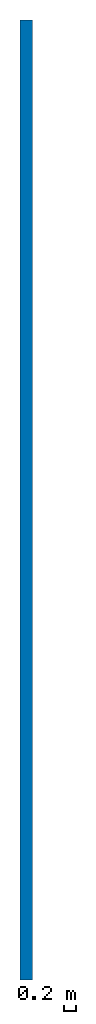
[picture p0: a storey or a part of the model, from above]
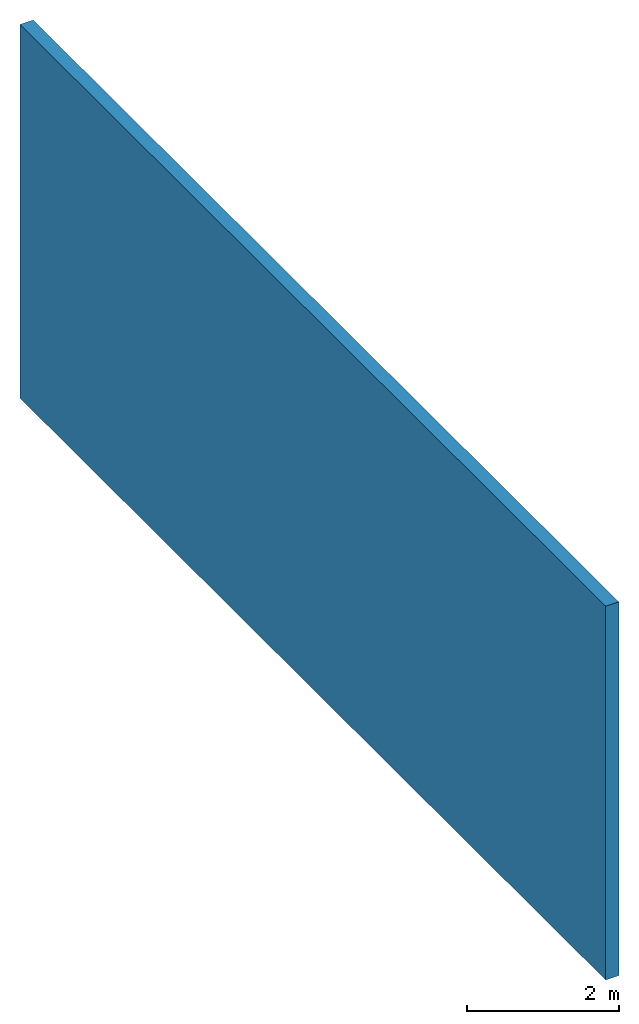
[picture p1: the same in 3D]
Properties of the parts of a building model (IFC2X3)

# File
Description: ViewDefinition [CoordinationView_V2.0]
File name: Project Number
Time: 2020-12-11T19:03:07
Written by: The EXPRESS Data Manager Version 5.02.0100.07 : 28 Aug 2013
Made in: 20190108_1515(x64) - Exporter 19.4.1.0 - Alternate UI 19.4.1.0
Comment: STEP Physical File produced by: The EXPRESS Data Manager Version 5.02.0100.07 : 28 Aug 2013 * Module: EDMstepFileFactory/EDMstandAlone * Creation date: Fri Dec 11 19:03:07 2020 * Host: OMEN-10 * Database: C:\Users\Eipm02\AppData\Local\Temp\{3D1B1A2C-8589-4297-B3EE-2A025A28AC27}\ifc * Database version: 5507 * Database creation date: Fri Dec 11 19:03:03 2020 * Schema: IFC2X3 * Model: DataRepository.ifc * Model creation date: Fri Dec 11 19:03:04 2020 * Header model: DataRepository.ifc_HeaderModel * Header model creation date: Fri Dec 11 19:03:04 2020 * EDMuser: sdai-user * EDMgroup: sdai-group * License ID and type: 5605 : Permanent license. Expiry date: * EDMstepFileFactory options: 020000

# IfcProject, Project Number
LongName: Project Name; Phase: Project Status

# IfcSite, Default
RefLatitude: 42, 21, 31, 181945; RefLongitude: -71, -3, -24, -263305; RefElevation: 57 m
Pset_ProductRequirements - Category: Project Information
Other - Category: Project Information; Client Name: Owner; Project Address: ## Street City, State Zip; Project Issue Date: Issue Date; Project Name: Project Name; Project Number: Project Number; Project Status: Project Status

# IfcBuilding
Pset_BuildingCommon - NumberOfStoreys: 2
Pset_ProductRequirements - Category: Project Information
Other - Category: Project Information; Client Name: Owner; Project Address: ## Street City, State Zip; Project Issue Date: Issue Date; Project Name: Project Name; Project Number: Project Number; Project Status: Project Status

# IfcBuildingStorey: Level:8mm Head (2)
Other(Type) - Category: Levels; Family Name: Level
Pset_ProductRequirements - Category: Levels
Dimensions - Computation Height: 0 m
Identity Data - Structural: no
Other - Category: Levels; Family: Level: 8mm Head; Family and Type: Level: 8mm Head; Type: Level: 8mm Head; Type Id: Level: 8mm Head
Constraints(Type) - Elevation Base: Project Base Point
Graphics(Type) - Color: 0; Line Pattern: Center; Line Weight: 1; Symbol: M_Level Head - Circle: M_Level Head - Circle; Symbol at End 1 Default: no; Symbol at End 2 Default: yes
Identity Data(Type) - Type Name: 8mm Head
Name | LongName | Elevation (m) | Pset_AirSideSystemInformation, Name = Pset_ProductRequirements, Name = Identity Data, Name | Constraints, Elevation (m) | Building Story
Level 1 | Level 1 | 1 | Altura interno | 2 | no
Level 2 | Level 2 | 7 | Level 2 | 9 | yes

# IfcWallStandardCase: Basic Wall:Generic - 200mm (2)
Type - PredefinedType: STANDARD; Material: Default Wall 0.2 m
Type - Analytical Properties - Absorptance: 0.1; Roughness: 1
Type - Construction - Function: Exterior; Width: 0.2 m; Wrapping at Inserts: Do not wrap
Type - Graphics - Coarse Scale Fill Color: 0
Type - Identity Data - Type Name: Generic - 200mm
Type - Other - Category: Walls; Family Name: Basic Wall
Type - Pset_ElementShading - Roughness: 0.3048 m
Type - Pset_ProductRequirements - Category: Walls
Type - Pset_QuantityTakeOff - Reference: Generic - 200mm
Type - Pset_ReinforcementBarPitchOfWall - Reference: Generic - 200mm
Type - Pset_WallCommon - Reference: Generic - 200mm; IsExternal: no
Constraints - Base Extension Distance: 0 m; Base is Attached: no; Base Offset: 0 m; Location Line: Wall Centerline; Related to Mass: no; Room Bounding: yes; Top Extension Distance: 0 m; Top is Attached: no; Top Offset: 0 m
Dimensions - Length: 15.4 m
Other - Family: Basic Wall: Generic - 200mm; Family and Type: Basic Wall: Generic - 200mm; Type: Basic Wall: Generic - 200mm; Type Id: Basic Wall: Generic - 200mm
Phasing - Phase Created: New Construction
Structural - Enable Analytical Model: no; Structural: no; Structural Usage: Non-bearing
Pset_QuantityTakeOff - sets with these values: 2
Pset_WallCommon - IsExternal: yes; ExtendToStructure: no; LoadBearing: no
Name (Basic Wall:Generic - 200mm:...) | In | Base Constraint | Top Constraint | Unconnected Height (m) | Area (m2) | Volume (m3)
202033 | Level 1 | Level: Level 1 | Level: Level 2 | 6 | 92.4 | 18.48
204346 | Level 2 | Level: Level 2 | Level: Level 3 | 2.5 | 38.5 | 7.7
